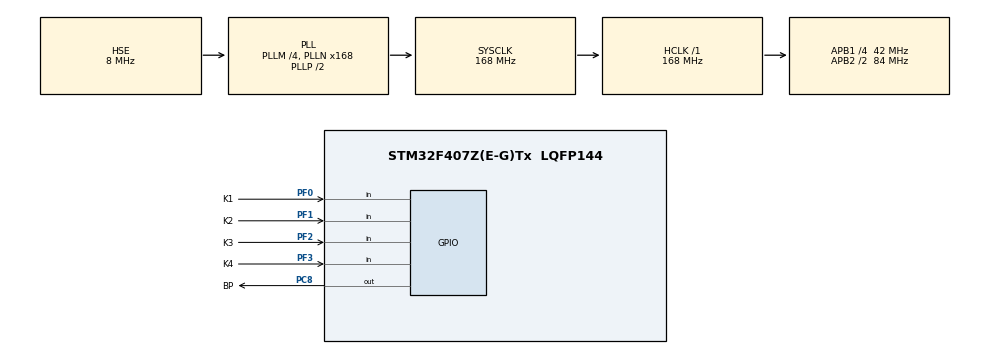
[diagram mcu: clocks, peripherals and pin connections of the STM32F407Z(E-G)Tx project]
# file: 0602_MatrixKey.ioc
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Mcu.Family=STM32F4
Mcu.Name=STM32F407Z(E-G)Tx
Mcu.Package=LQFP144
NVIC.PriorityGroup=NVIC_PRIORITYGROUP_4
PA13.Mode=Serial_Wire
PA13.Signal=SYS_JTMS-SWDIO
PA14.Mode=Serial_Wire
PA14.Signal=SYS_JTCK-SWCLK
PC14-OSC32_IN.Mode=LSE-External-Oscillator
PC14-OSC32_IN.Signal=RCC_OSC32_IN
PC15-OSC32_OUT.Mode=LSE-External-Oscillator
PC15-OSC32_OUT.Signal=RCC_OSC32_OUT
PC8.GPIO_Label=BP
PC8.PinState=GPIO_PIN_SET
PC8.Signal=GPIO_Output
PF0.GPIO_Label=K1
PF0.GPIO_PuPd=GPIO_PULLUP
PF0.Signal=GPIO_Input
PF1.GPIO_Label=K2
PF1.GPIO_PuPd=GPIO_PULLUP
PF1.Signal=GPIO_Input
PF2.GPIO_Label=K3
PF2.GPIO_PuPd=GPIO_PULLUP
PF2.Signal=GPIO_Input
PF3.GPIO_Label=K4
PF3.GPIO_PuPd=GPIO_PULLUP
PF3.Signal=GPIO_Input
PH0-OSC_IN.Mode=HSE-External-Oscillator
PH0-OSC_IN.Signal=RCC_OSC_IN
PH1-OSC_OUT.Mode=HSE-External-Oscillator
PH1-OSC_OUT.Signal=RCC_OSC_OUT
ProjectManager.HeapSize=0x200
ProjectManager.StackSize=0x400
ProjectManager.TargetToolchain=MDK-ARM V5.32
RCC.48MHZClocksFreq_Value=84000000
RCC.AHBFreq_Value=168000000
RCC.APB1CLKDivider=RCC_HCLK_DIV4
RCC.APB1Freq_Value=42000000
RCC.APB1TimFreq_Value=84000000
RCC.APB2CLKDivider=RCC_HCLK_DIV2
RCC.APB2Freq_Value=84000000
RCC.APB2TimFreq_Value=168000000
RCC.CortexFreq_Value=168000000
RCC.HCLKFreq_Value=168000000
RCC.HSE_VALUE=8000000
RCC.HSI_VALUE=16000000
RCC.PLLM=4
RCC.PLLN=168
RCC.PLLSourceVirtual=RCC_PLLSOURCE_HSE
RCC.SYSCLKFreq_VALUE=168000000
RCC.SYSCLKSource=RCC_SYSCLKSOURCE_PLLCLK
RCC.VCOOutputFreq_Value=336000000
board=custom

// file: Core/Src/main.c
/* USER CODE BEGIN Header */
/**
  ******************************************************************************
  * @file           : main.c
  * @brief          : Main program body
  ******************************************************************************
  * @attention
  *
  * Copyright (c) 2026 STMicroelectronics.
  * All rights reserved.
  *
  * This software is licensed under terms that can be found in the LICENSE file
  * in the root directory of this software component.
  * If no LICENSE file comes with this software, it is provided AS-IS.
  ******************************************************************************
  */
/* USER CODE END Header */
#include "main.h"

void SystemClock_Config(void);
static void MX_GPIO_Init(void);

int main(void)
{
  /* USER CODE BEGIN 1 */
	uint16_t i, KeyVal=0;
	uint8_t PreLine[3]={2,0,1};
  /* USER CODE END 1 */

  /* MCU Configuration--------------------------------------------------------*/

  /* Reset of all peripherals, Initializes the Flash interface and the Systick. */
  HAL_Init();

  /* Configure the system clock */
  SystemClock_Config();

  /* Initialize all configured peripherals */
  MX_GPIO_Init();

  /* Infinite loop */
  /* USER CODE BEGIN WHILE */
  while (1)
  {
		for(i=0;i<3;i++)
		{
			if((GPIOE->IDR & 0x0F)!=0x0F)
			{
				HAL_Delay(16);
				if((GPIOE->IDR & 0x0F)!=0x0F)
				{
					switch((GPIOE->IDR & 0x0F))
					{
						case 0x0E: KeyVal=4*PreLine[i]+1;break;
						case 0x0D: KeyVal=4*PreLine[i]+2;break;
						case 0x0B: KeyVal=4*PreLine[i]+3;break;
						case 0x07: KeyVal=4*PreLine[i]+4;break;
						default : break;
					}
				}
			}
			GPIOE->ODR= ~(1<<(i+4));
		}
		GPIOF->ODR= ~( (KeyVal/10 <<4) + KeyVal%10 );
    /* USER CODE END WHILE */

  }
}

void SystemClock_Config(void)
{
  RCC_OscInitTypeDef RCC_OscInitStruct = {0};
  RCC_ClkInitTypeDef RCC_ClkInitStruct = {0};

  /** Configure the main internal regulator output voltage
  */
  __HAL_RCC_PWR_CLK_ENABLE();
  __HAL_PWR_VOLTAGESCALING_CONFIG(PWR_REGULATOR_VOLTAGE_SCALE1);

  /** Initializes the RCC Oscillators according to the specified parameters
  * in the RCC_OscInitTypeDef structure.
  */
  RCC_OscInitStruct.OscillatorType = RCC_OSCILLATORTYPE_HSE;
  RCC_OscInitStruct.HSEState = RCC_HSE_ON;
  RCC_OscInitStruct.PLL.PLLState = RCC_PLL_ON;
  RCC_OscInitStruct.PLL.PLLSource = RCC_PLLSOURCE_HSE;
  RCC_OscInitStruct.PLL.PLLM = 4;
  RCC_OscInitStruct.PLL.PLLN = 168;
  RCC_OscInitStruct.PLL.PLLP = RCC_PLLP_DIV2;
  RCC_OscInitStruct.PLL.PLLQ = 4;
  if (HAL_RCC_OscConfig(&RCC_OscInitStruct) != HAL_OK)
  {
    Error_Handler();
  }

  /** Initializes the CPU, AHB and APB buses clocks
  */
  RCC_ClkInitStruct.ClockType = RCC_CLOCKTYPE_HCLK|RCC_CLOCKTYPE_SYSCLK
                              |RCC_CLOCKTYPE_PCLK1|RCC_CLOCKTYPE_PCLK2;
  RCC_ClkInitStruct.SYSCLKSource = RCC_SYSCLKSOURCE_PLLCLK;
  RCC_ClkInitStruct.AHBCLKDivider = RCC_SYSCLK_DIV1;
  RCC_ClkInitStruct.APB1CLKDivider = RCC_HCLK_DIV4;
  RCC_ClkInitStruct.APB2CLKDivider = RCC_HCLK_DIV2;

  if (HAL_RCC_ClockConfig(&RCC_ClkInitStruct, FLASH_LATENCY_5) != HAL_OK)
  {
    Error_Handler();
  }
}

static void MX_GPIO_Init(void)
{
  GPIO_InitTypeDef GPIO_InitStruct = {0};

  /* GPIO Ports Clock Enable */
  __HAL_RCC_GPIOE_CLK_ENABLE();
  __HAL_RCC_GPIOF_CLK_ENABLE();
  __HAL_RCC_GPIOH_CLK_ENABLE();

  /*Configure GPIO pin Output Level */
  HAL_GPIO_WritePin(GPIOE, GPIO_PIN_4|GPIO_PIN_5|GPIO_PIN_6, GPIO_PIN_SET);
  HAL_GPIO_WritePin(GPIOF, GPIO_PIN_0|GPIO_PIN_1|GPIO_PIN_2|GPIO_PIN_3
                          |GPIO_PIN_4|GPIO_PIN_5|GPIO_PIN_6|GPIO_PIN_7, GPIO_PIN_SET);

  /*Configure GPIO pins : PE0 PE1 PE2 PE3 */
  GPIO_InitStruct.Pin = GPIO_PIN_0|GPIO_PIN_1|GPIO_PIN_2|GPIO_PIN_3;
  GPIO_InitStruct.Mode = GPIO_MODE_INPUT;
  GPIO_InitStruct.Pull = GPIO_PULLUP;
  HAL_GPIO_Init(GPIOE, &GPIO_InitStruct);

  /*Configure GPIO pins : PE4 PE5 PE6 */
  GPIO_InitStruct.Pin = GPIO_PIN_4|GPIO_PIN_5|GPIO_PIN_6;
  GPIO_InitStruct.Mode = GPIO_MODE_OUTPUT_PP;
  GPIO_InitStruct.Pull = GPIO_NOPULL;
  GPIO_InitStruct.Speed = GPIO_SPEED_FREQ_LOW;
  HAL_GPIO_Init(GPIOE, &GPIO_InitStruct);

  /*Configure GPIO pins : PF0-PF7 LED?? */
  GPIO_InitStruct.Pin = GPIO_PIN_0|GPIO_PIN_1|GPIO_PIN_2|GPIO_PIN_3
                          |GPIO_PIN_4|GPIO_PIN_5|GPIO_PIN_6|GPIO_PIN_7;
  GPIO_InitStruct.Mode = GPIO_MODE_OUTPUT_PP;
  GPIO_InitStruct.Pull = GPIO_NOPULL;
  GPIO_InitStruct.Speed = GPIO_SPEED_FREQ_LOW;
  HAL_GPIO_Init(GPIOF, &GPIO_InitStruct);

}

void Error_Handler(void)
{
  __disable_irq();
  while (1)
  {
  }
}
